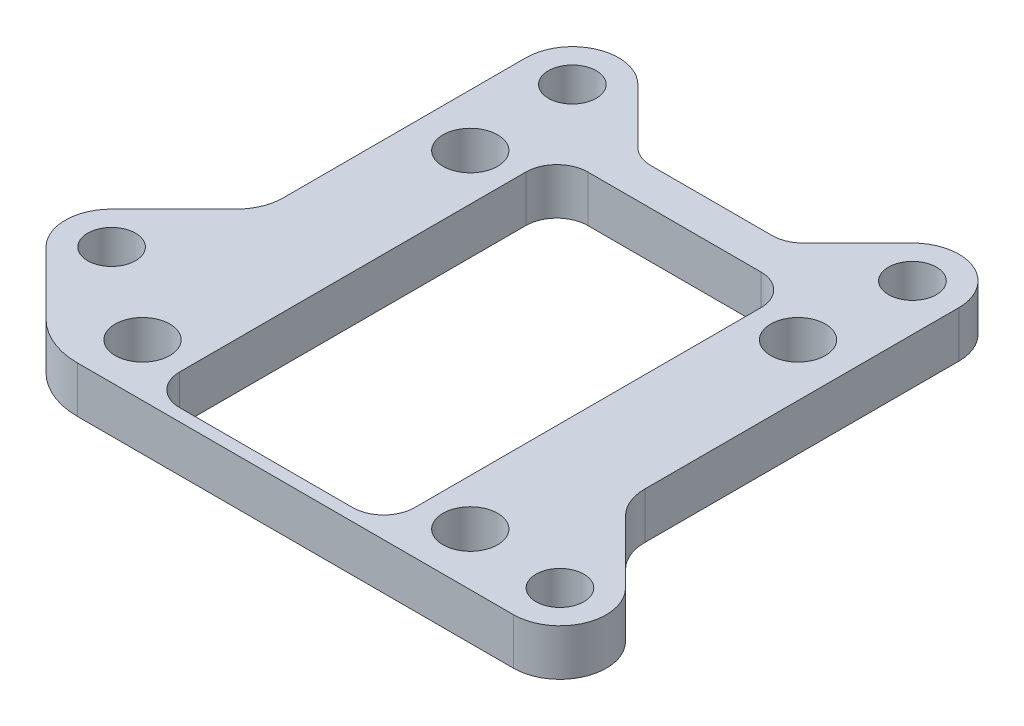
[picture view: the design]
ISO-10303-21;
HEADER;
FILE_DESCRIPTION(('STEP AP214'),'2;1');
FILE_NAME('part.step','',(''),(''),'','','');
FILE_SCHEMA(('AUTOMOTIVE_DESIGN { 1 0 10303 214 1 1 1 1 }'));
ENDSEC;
DATA;
#1=APPLICATION_CONTEXT('core data for automotive mechanical design processes');
#2=APPLICATION_PROTOCOL_DEFINITION('international standard','automotive_design',2000,#1);
#3=PRODUCT_CONTEXT('',#1,'mechanical');
#4=PRODUCT('Part','Part','',(#3));
#5=PRODUCT_RELATED_PRODUCT_CATEGORY('part','',(#4));
#6=PRODUCT_DEFINITION_FORMATION('','',#4);
#7=PRODUCT_DEFINITION_CONTEXT('part definition',#1,'design');
#8=PRODUCT_DEFINITION('design','',#6,#7);
#9=PRODUCT_DEFINITION_SHAPE('','',#8);
#10=(LENGTH_UNIT() NAMED_UNIT(*) SI_UNIT(.MILLI.,.METRE.));
#11=(NAMED_UNIT(*) PLANE_ANGLE_UNIT() SI_UNIT($,.RADIAN.));
#12=(NAMED_UNIT(*) SI_UNIT($,.STERADIAN.) SOLID_ANGLE_UNIT());
#13=UNCERTAINTY_MEASURE_WITH_UNIT(LENGTH_MEASURE(1.E-05),#10,'distance_accuracy_value','');
#14=(GEOMETRIC_REPRESENTATION_CONTEXT(3) GLOBAL_UNCERTAINTY_ASSIGNED_CONTEXT((#13)) GLOBAL_UNIT_ASSIGNED_CONTEXT((#10,
#11,#12)) REPRESENTATION_CONTEXT('',''));
#15=CARTESIAN_POINT('',(0.,0.,0.));
#16=DIRECTION('',(0.,0.,1.));
#17=DIRECTION('',(1.,0.,0.));
#18=AXIS2_PLACEMENT_3D('',#15,#16,#17);
#19=CARTESIAN_POINT('',(6.23717984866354,4.7625,-27.94));
#20=DIRECTION('',(0.,-1.,0.));
#21=DIRECTION('',(0.,0.,-1.));
#22=AXIS2_PLACEMENT_3D('',#19,#20,#21);
#23=PLANE('',#22);
#24=CARTESIAN_POINT('',(-17.4625,4.7625,-27.94));
#25=DIRECTION('',(0.,1.,0.));
#26=DIRECTION('',(0.,0.,1.));
#27=AXIS2_PLACEMENT_3D('',#24,#25,#26);
#28=CIRCLE('',#27,2.45744999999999);
#29=CARTESIAN_POINT('',(-17.4625,4.7625,-25.48255));
#30=VERTEX_POINT('',#29);
#31=EDGE_CURVE('E810',#30,#30,#28,.T.);
#32=ORIENTED_EDGE('',*,*,#31,.F.);
#33=EDGE_LOOP('',(#32));
#34=FACE_BOUND('',#33,.T.);
#35=CARTESIAN_POINT('',(17.4625,4.7625,-27.94));
#36=DIRECTION('',(0.,1.,0.));
#37=DIRECTION('',(0.,0.,1.));
#38=AXIS2_PLACEMENT_3D('',#35,#36,#37);
#39=CIRCLE('',#38,2.45744999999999);
#40=CARTESIAN_POINT('',(17.4625,4.7625,-25.48255));
#41=VERTEX_POINT('',#40);
#42=EDGE_CURVE('E812',#41,#41,#39,.T.);
#43=ORIENTED_EDGE('',*,*,#42,.F.);
#44=EDGE_LOOP('',(#43));
#45=FACE_BOUND('',#44,.T.);
#46=CARTESIAN_POINT('',(-26.67,4.7625,10.16));
#47=DIRECTION('',(0.,1.,0.));
#48=DIRECTION('',(0.,0.,1.));
#49=AXIS2_PLACEMENT_3D('',#46,#47,#48);
#50=CIRCLE('',#49,2.45744999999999);
#51=CARTESIAN_POINT('',(-26.67,4.7625,12.61745));
#52=VERTEX_POINT('',#51);
#53=EDGE_CURVE('E820',#52,#52,#50,.T.);
#54=ORIENTED_EDGE('',*,*,#53,.F.);
#55=EDGE_LOOP('',(#54));
#56=FACE_BOUND('',#55,.T.);
#57=CARTESIAN_POINT('',(26.67,4.7625,17.4625));
#58=DIRECTION('',(0.,1.,0.));
#59=DIRECTION('',(0.,0.,1.));
#60=AXIS2_PLACEMENT_3D('',#57,#58,#59);
#61=CIRCLE('',#60,2.45744999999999);
#62=CARTESIAN_POINT('',(26.67,4.7625,19.91995));
#63=VERTEX_POINT('',#62);
#64=EDGE_CURVE('E826',#63,#63,#61,.T.);
#65=ORIENTED_EDGE('',*,*,#64,.F.);
#66=EDGE_LOOP('',(#65));
#67=FACE_BOUND('',#66,.T.);
#68=CARTESIAN_POINT('',(-16.8275,4.7625,-16.8275));
#69=DIRECTION('',(0.,1.,0.));
#70=DIRECTION('',(0.,0.,1.));
#71=AXIS2_PLACEMENT_3D('',#68,#69,#70);
#72=CIRCLE('',#71,2.80669999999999);
#73=CARTESIAN_POINT('',(-16.8275,4.7625,-14.0208));
#74=VERTEX_POINT('',#73);
#75=EDGE_CURVE('E832',#74,#74,#72,.T.);
#76=ORIENTED_EDGE('',*,*,#75,.F.);
#77=EDGE_LOOP('',(#76));
#78=FACE_BOUND('',#77,.T.);
#79=CARTESIAN_POINT('',(16.8275,4.7625,16.8275));
#80=DIRECTION('',(0.,1.,0.));
#81=DIRECTION('',(0.,0.,1.));
#82=AXIS2_PLACEMENT_3D('',#79,#80,#81);
#83=CIRCLE('',#82,2.80669999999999);
#84=CARTESIAN_POINT('',(16.8275,4.7625,19.6342));
#85=VERTEX_POINT('',#84);
#86=EDGE_CURVE('E838',#85,#85,#83,.T.);
#87=ORIENTED_EDGE('',*,*,#86,.F.);
#88=EDGE_LOOP('',(#87));
#89=FACE_BOUND('',#88,.T.);
#90=CARTESIAN_POINT('',(16.8275,4.7625,-16.8275));
#91=DIRECTION('',(0.,1.,0.));
#92=DIRECTION('',(0.,0.,1.));
#93=AXIS2_PLACEMENT_3D('',#90,#91,#92);
#94=CIRCLE('',#93,2.80669999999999);
#95=CARTESIAN_POINT('',(16.8275,4.7625,-14.0208));
#96=VERTEX_POINT('',#95);
#97=EDGE_CURVE('E844',#96,#96,#94,.T.);
#98=ORIENTED_EDGE('',*,*,#97,.F.);
#99=EDGE_LOOP('',(#98));
#100=FACE_BOUND('',#99,.T.);
#101=CARTESIAN_POINT('',(6.23717984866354,4.7625,-27.94));
#102=DIRECTION('',(0.,-1.,0.));
#103=DIRECTION('',(0.,0.,-1.));
#104=AXIS2_PLACEMENT_3D('',#101,#102,#103);
#105=CIRCLE('',#104,3.175);
#106=CARTESIAN_POINT('',(8.48224387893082,4.7625,-25.6949359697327));
#107=VERTEX_POINT('',#106);
#108=CARTESIAN_POINT('',(6.23717984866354,4.7625,-24.765));
#109=VERTEX_POINT('',#108);
#110=EDGE_CURVE('E276',#107,#109,#105,.T.);
#111=ORIENTED_EDGE('',*,*,#110,.T.);
#112=DIRECTION('',(-1.,0.,0.));
#113=VECTOR('',#112,1.);
#114=CARTESIAN_POINT('',(-6.23717984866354,4.7625,-24.765));
#115=LINE('',#114,#113);
#116=CARTESIAN_POINT('',(-6.23717984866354,4.7625,-24.765));
#117=VERTEX_POINT('',#116);
#118=EDGE_CURVE('E279',#109,#117,#115,.T.);
#119=ORIENTED_EDGE('',*,*,#118,.T.);
#120=CARTESIAN_POINT('',(-6.23717984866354,4.7625,-27.94));
#121=DIRECTION('',(0.,-1.,0.));
#122=DIRECTION('',(0.,0.,1.));
#123=AXIS2_PLACEMENT_3D('',#120,#121,#122);
#124=CIRCLE('',#123,3.17500000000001);
#125=CARTESIAN_POINT('',(-8.48224387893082,4.7625,-25.6949359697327));
#126=VERTEX_POINT('',#125);
#127=EDGE_CURVE('E282',#117,#126,#124,.T.);
#128=ORIENTED_EDGE('',*,*,#127,.T.);
#129=DIRECTION('',(-0.707106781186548,0.,-0.707106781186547));
#130=VECTOR('',#129,1.);
#131=CARTESIAN_POINT('',(-8.48224387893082,4.7625,-25.6949359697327));
#132=LINE('',#131,#130);
#133=CARTESIAN_POINT('',(-14.0949039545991,4.7625,-31.3075960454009));
#134=VERTEX_POINT('',#133);
#135=EDGE_CURVE('E284',#126,#134,#132,.T.);
#136=ORIENTED_EDGE('',*,*,#135,.T.);
#137=CARTESIAN_POINT('',(-17.4625,4.7625,-27.94));
#138=DIRECTION('',(0.,1.,0.));
#139=DIRECTION('',(0.,0.,-1.));
#140=AXIS2_PLACEMENT_3D('',#137,#138,#139);
#141=CIRCLE('',#140,4.7625);
#142=CARTESIAN_POINT('',(-22.225,4.7625,-27.94));
#143=VERTEX_POINT('',#142);
#144=EDGE_CURVE('E286',#134,#143,#141,.T.);
#145=ORIENTED_EDGE('',*,*,#144,.T.);
#146=DIRECTION('',(0.,0.,1.));
#147=VECTOR('',#146,1.);
#148=CARTESIAN_POINT('',(-22.225,4.7625,-2.99288418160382));
#149=LINE('',#148,#147);
#150=CARTESIAN_POINT('',(-22.225,4.7625,-2.99288418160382));
#151=VERTEX_POINT('',#150);
#152=EDGE_CURVE('E288',#143,#151,#149,.T.);
#153=ORIENTED_EDGE('',*,*,#152,.T.);
#154=CARTESIAN_POINT('',(-26.9875,4.7625,-2.99288418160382));
#155=DIRECTION('',(0.,-1.,0.));
#156=DIRECTION('',(0.,0.,-1.));
#157=AXIS2_PLACEMENT_3D('',#154,#155,#156);
#158=CIRCLE('',#157,4.76249999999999);
#159=CARTESIAN_POINT('',(-23.619903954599,4.7625,0.374711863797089));
#160=VERTEX_POINT('',#159);
#161=EDGE_CURVE('E290',#151,#160,#158,.T.);
#162=ORIENTED_EDGE('',*,*,#161,.T.);
#163=DIRECTION('',(-0.707106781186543,0.,0.707106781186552));
#164=VECTOR('',#163,1.);
#165=CARTESIAN_POINT('',(-23.619903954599,4.7625,0.374711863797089));
#166=LINE('',#165,#164);
#167=CARTESIAN_POINT('',(-30.0375960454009,4.7625,6.79240395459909));
#168=VERTEX_POINT('',#167);
#169=EDGE_CURVE('E292',#160,#168,#166,.T.);
#170=ORIENTED_EDGE('',*,*,#169,.T.);
#171=CARTESIAN_POINT('',(-26.67,4.7625,10.16));
#172=DIRECTION('',(0.,1.,0.));
#173=DIRECTION('',(0.,0.,-1.));
#174=AXIS2_PLACEMENT_3D('',#171,#172,#173);
#175=CIRCLE('',#174,4.7625);
#176=CARTESIAN_POINT('',(-30.0375960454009,4.7625,13.5275960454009));
#177=VERTEX_POINT('',#176);
#178=EDGE_CURVE('E294',#168,#177,#175,.T.);
#179=ORIENTED_EDGE('',*,*,#178,.T.);
#180=DIRECTION('',(0.707106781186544,0.,0.707106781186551));
#181=VECTOR('',#180,1.);
#182=CARTESIAN_POINT('',(-30.0375960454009,4.7625,13.5275960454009));
#183=LINE('',#182,#181);
#184=CARTESIAN_POINT('',(-23.619903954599,4.7625,19.9452881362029));
#185=VERTEX_POINT('',#184);
#186=EDGE_CURVE('E296',#177,#185,#183,.T.);
#187=ORIENTED_EDGE('',*,*,#186,.T.);
#188=CARTESIAN_POINT('',(-18.1161926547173,4.7625,14.4415768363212));
#189=DIRECTION('',(0.,1.,0.));
#190=DIRECTION('',(0.,0.,-1.));
#191=AXIS2_PLACEMENT_3D('',#188,#189,#190);
#192=CIRCLE('',#191,7.78342316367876);
#193=CARTESIAN_POINT('',(-18.1161926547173,4.7625,22.225));
#194=VERTEX_POINT('',#193);
#195=EDGE_CURVE('E298',#185,#194,#192,.T.);
#196=ORIENTED_EDGE('',*,*,#195,.T.);
#197=DIRECTION('',(1.,0.,0.));
#198=VECTOR('',#197,1.);
#199=CARTESIAN_POINT('',(-18.1161926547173,4.7625,22.225));
#200=LINE('',#199,#198);
#201=CARTESIAN_POINT('',(26.67,4.7625,22.225));
#202=VERTEX_POINT('',#201);
#203=EDGE_CURVE('E300',#194,#202,#200,.T.);
#204=ORIENTED_EDGE('',*,*,#203,.T.);
#205=CARTESIAN_POINT('',(26.67,4.7625,17.4625));
#206=DIRECTION('',(0.,1.,0.));
#207=DIRECTION('',(0.,0.,1.));
#208=AXIS2_PLACEMENT_3D('',#205,#206,#207);
#209=CIRCLE('',#208,4.7625);
#210=CARTESIAN_POINT('',(30.037596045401,4.7625,14.0949039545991));
#211=VERTEX_POINT('',#210);
#212=EDGE_CURVE('E302',#202,#211,#209,.T.);
#213=ORIENTED_EDGE('',*,*,#212,.T.);
#214=DIRECTION('',(-0.707106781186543,0.,-0.707106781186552));
#215=VECTOR('',#214,1.);
#216=CARTESIAN_POINT('',(23.619903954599,4.7625,7.67721186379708));
#217=LINE('',#216,#215);
#218=CARTESIAN_POINT('',(23.619903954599,4.7625,7.67721186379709));
#219=VERTEX_POINT('',#218);
#220=EDGE_CURVE('E304',#211,#219,#217,.T.);
#221=ORIENTED_EDGE('',*,*,#220,.T.);
#222=CARTESIAN_POINT('',(26.9875,4.7625,4.30961581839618));
#223=DIRECTION('',(0.,-1.,0.));
#224=DIRECTION('',(0.,0.,-1.));
#225=AXIS2_PLACEMENT_3D('',#222,#223,#224);
#226=CIRCLE('',#225,4.7625);
#227=CARTESIAN_POINT('',(22.225,4.7625,4.30961581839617));
#228=VERTEX_POINT('',#227);
#229=EDGE_CURVE('E306',#219,#228,#226,.T.);
#230=ORIENTED_EDGE('',*,*,#229,.T.);
#231=DIRECTION('',(0.,0.,-1.));
#232=VECTOR('',#231,1.);
#233=CARTESIAN_POINT('',(22.225,4.7625,4.30961581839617));
#234=LINE('',#233,#232);
#235=CARTESIAN_POINT('',(22.225,4.7625,-27.94));
#236=VERTEX_POINT('',#235);
#237=EDGE_CURVE('E308',#228,#236,#234,.T.);
#238=ORIENTED_EDGE('',*,*,#237,.T.);
#239=CARTESIAN_POINT('',(17.4625,4.7625,-27.94));
#240=DIRECTION('',(0.,1.,0.));
#241=DIRECTION('',(0.,0.,-1.));
#242=AXIS2_PLACEMENT_3D('',#239,#240,#241);
#243=CIRCLE('',#242,4.7625);
#244=CARTESIAN_POINT('',(14.0949039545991,4.7625,-31.3075960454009));
#245=VERTEX_POINT('',#244);
#246=EDGE_CURVE('E310',#236,#245,#243,.T.);
#247=ORIENTED_EDGE('',*,*,#246,.T.);
#248=DIRECTION('',(-0.707106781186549,0.,0.707106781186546));
#249=VECTOR('',#248,1.);
#250=CARTESIAN_POINT('',(8.48224387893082,4.7625,-25.6949359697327));
#251=LINE('',#250,#249);
#252=EDGE_CURVE('E312',#245,#107,#251,.T.);
#253=ORIENTED_EDGE('',*,*,#252,.T.);
#254=EDGE_LOOP('',(#111,#119,#128,#136,#145,#153,#162,#170,#179,#187,#196,#204,#213,#221,#230,
#238,#247,#253));
#255=FACE_BOUND('',#254,.T.);
#256=CARTESIAN_POINT('',(-8.89,4.7625,-17.78));
#257=DIRECTION('',(0.,1.,0.));
#258=DIRECTION('',(0.,0.,-1.));
#259=AXIS2_PLACEMENT_3D('',#256,#257,#258);
#260=CIRCLE('',#259,3.175);
#261=CARTESIAN_POINT('',(-8.88999999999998,4.7625,-20.955));
#262=VERTEX_POINT('',#261);
#263=CARTESIAN_POINT('',(-12.065,4.7625,-17.78));
#264=VERTEX_POINT('',#263);
#265=EDGE_CURVE('E208',#262,#264,#260,.T.);
#266=ORIENTED_EDGE('',*,*,#265,.F.);
#267=DIRECTION('',(-1.,0.,0.));
#268=VECTOR('',#267,1.);
#269=CARTESIAN_POINT('',(-8.88999999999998,4.7625,-20.955));
#270=LINE('',#269,#268);
#271=CARTESIAN_POINT('',(8.88999999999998,4.7625,-20.955));
#272=VERTEX_POINT('',#271);
#273=EDGE_CURVE('E243',#272,#262,#270,.T.);
#274=ORIENTED_EDGE('',*,*,#273,.F.);
#275=CARTESIAN_POINT('',(8.89,4.7625,-17.78));
#276=DIRECTION('',(0.,1.,0.));
#277=DIRECTION('',(0.,0.,-1.));
#278=AXIS2_PLACEMENT_3D('',#275,#276,#277);
#279=CIRCLE('',#278,3.175);
#280=CARTESIAN_POINT('',(12.065,4.7625,-17.78));
#281=VERTEX_POINT('',#280);
#282=EDGE_CURVE('E241',#281,#272,#279,.T.);
#283=ORIENTED_EDGE('',*,*,#282,.F.);
#284=DIRECTION('',(0.,0.,-1.));
#285=VECTOR('',#284,1.);
#286=CARTESIAN_POINT('',(12.065,4.7625,17.78));
#287=LINE('',#286,#285);
#288=CARTESIAN_POINT('',(12.065,4.7625,17.78));
#289=VERTEX_POINT('',#288);
#290=EDGE_CURVE('E239',#289,#281,#287,.T.);
#291=ORIENTED_EDGE('',*,*,#290,.F.);
#292=CARTESIAN_POINT('',(8.89,4.7625,17.78));
#293=DIRECTION('',(0.,1.,0.));
#294=DIRECTION('',(0.,0.,1.));
#295=AXIS2_PLACEMENT_3D('',#292,#293,#294);
#296=CIRCLE('',#295,3.175);
#297=CARTESIAN_POINT('',(8.88999999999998,4.7625,20.955));
#298=VERTEX_POINT('',#297);
#299=EDGE_CURVE('E237',#298,#289,#296,.T.);
#300=ORIENTED_EDGE('',*,*,#299,.F.);
#301=DIRECTION('',(1.,0.,0.));
#302=VECTOR('',#301,1.);
#303=CARTESIAN_POINT('',(-8.88999999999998,4.7625,20.955));
#304=LINE('',#303,#302);
#305=CARTESIAN_POINT('',(-8.88999999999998,4.7625,20.955));
#306=VERTEX_POINT('',#305);
#307=EDGE_CURVE('E232',#306,#298,#304,.T.);
#308=ORIENTED_EDGE('',*,*,#307,.F.);
#309=CARTESIAN_POINT('',(-8.89,4.7625,17.78));
#310=DIRECTION('',(0.,1.,0.));
#311=DIRECTION('',(0.,0.,-1.));
#312=AXIS2_PLACEMENT_3D('',#309,#310,#311);
#313=CIRCLE('',#312,3.175);
#314=CARTESIAN_POINT('',(-12.065,4.7625,17.78));
#315=VERTEX_POINT('',#314);
#316=EDGE_CURVE('E230',#315,#306,#313,.T.);
#317=ORIENTED_EDGE('',*,*,#316,.F.);
#318=DIRECTION('',(0.,0.,1.));
#319=VECTOR('',#318,1.);
#320=CARTESIAN_POINT('',(-12.065,4.7625,17.78));
#321=LINE('',#320,#319);
#322=EDGE_CURVE('E216',#264,#315,#321,.T.);
#323=ORIENTED_EDGE('',*,*,#322,.F.);
#324=EDGE_LOOP('',(#266,#274,#283,#291,#300,#308,#317,#323));
#325=FACE_BOUND('',#324,.T.);
#326=CARTESIAN_POINT('',(-16.8275,4.7625,16.8275));
#327=DIRECTION('',(0.,1.,0.));
#328=DIRECTION('',(0.,0.,1.));
#329=AXIS2_PLACEMENT_3D('',#326,#327,#328);
#330=CIRCLE('',#329,2.80669999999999);
#331=CARTESIAN_POINT('',(-16.8275,4.7625,19.6342));
#332=VERTEX_POINT('',#331);
#333=EDGE_CURVE('E850',#332,#332,#330,.T.);
#334=ORIENTED_EDGE('',*,*,#333,.F.);
#335=EDGE_LOOP('',(#334));
#336=FACE_BOUND('',#335,.T.);
#337=ADVANCED_FACE('F35',(#34,#45,#56,#67,#78,#89,#100,#255,#325,#336),#23,.F.);
#338=CARTESIAN_POINT('',(6.23717984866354,0.,-27.94));
#339=DIRECTION('',(0.,-1.,0.));
#340=DIRECTION('',(0.,0.,-1.));
#341=AXIS2_PLACEMENT_3D('',#338,#339,#340);
#342=PLANE('',#341);
#343=CARTESIAN_POINT('',(-17.4625,0.,-27.94));
#344=DIRECTION('',(0.,1.,0.));
#345=DIRECTION('',(0.,0.,1.));
#346=AXIS2_PLACEMENT_3D('',#343,#344,#345);
#347=CIRCLE('',#346,2.45745);
#348=CARTESIAN_POINT('',(-17.4625,0.,-25.48255));
#349=VERTEX_POINT('',#348);
#350=EDGE_CURVE('E808',#349,#349,#347,.T.);
#351=ORIENTED_EDGE('',*,*,#350,.T.);
#352=EDGE_LOOP('',(#351));
#353=FACE_BOUND('',#352,.T.);
#354=CARTESIAN_POINT('',(17.4625,0.,-27.94));
#355=DIRECTION('',(0.,1.,0.));
#356=DIRECTION('',(0.,0.,1.));
#357=AXIS2_PLACEMENT_3D('',#354,#355,#356);
#358=CIRCLE('',#357,2.45745);
#359=CARTESIAN_POINT('',(17.4625,0.,-25.48255));
#360=VERTEX_POINT('',#359);
#361=EDGE_CURVE('E817',#360,#360,#358,.T.);
#362=ORIENTED_EDGE('',*,*,#361,.T.);
#363=EDGE_LOOP('',(#362));
#364=FACE_BOUND('',#363,.T.);
#365=CARTESIAN_POINT('',(-26.67,0.,10.16));
#366=DIRECTION('',(0.,1.,0.));
#367=DIRECTION('',(0.,0.,1.));
#368=AXIS2_PLACEMENT_3D('',#365,#366,#367);
#369=CIRCLE('',#368,2.45745);
#370=CARTESIAN_POINT('',(-26.67,0.,12.61745));
#371=VERTEX_POINT('',#370);
#372=EDGE_CURVE('E823',#371,#371,#369,.T.);
#373=ORIENTED_EDGE('',*,*,#372,.T.);
#374=EDGE_LOOP('',(#373));
#375=FACE_BOUND('',#374,.T.);
#376=CARTESIAN_POINT('',(26.67,0.,17.4625));
#377=DIRECTION('',(0.,1.,0.));
#378=DIRECTION('',(0.,0.,1.));
#379=AXIS2_PLACEMENT_3D('',#376,#377,#378);
#380=CIRCLE('',#379,2.45745);
#381=CARTESIAN_POINT('',(26.67,0.,19.91995));
#382=VERTEX_POINT('',#381);
#383=EDGE_CURVE('E829',#382,#382,#380,.T.);
#384=ORIENTED_EDGE('',*,*,#383,.T.);
#385=EDGE_LOOP('',(#384));
#386=FACE_BOUND('',#385,.T.);
#387=CARTESIAN_POINT('',(-16.8275,0.,-16.8275));
#388=DIRECTION('',(0.,1.,0.));
#389=DIRECTION('',(0.,0.,1.));
#390=AXIS2_PLACEMENT_3D('',#387,#388,#389);
#391=CIRCLE('',#390,2.8067);
#392=CARTESIAN_POINT('',(-16.8275,0.,-14.0208));
#393=VERTEX_POINT('',#392);
#394=EDGE_CURVE('E835',#393,#393,#391,.T.);
#395=ORIENTED_EDGE('',*,*,#394,.T.);
#396=EDGE_LOOP('',(#395));
#397=FACE_BOUND('',#396,.T.);
#398=CARTESIAN_POINT('',(16.8275,0.,16.8275));
#399=DIRECTION('',(0.,1.,0.));
#400=DIRECTION('',(0.,0.,1.));
#401=AXIS2_PLACEMENT_3D('',#398,#399,#400);
#402=CIRCLE('',#401,2.8067);
#403=CARTESIAN_POINT('',(16.8275,0.,19.6342));
#404=VERTEX_POINT('',#403);
#405=EDGE_CURVE('E841',#404,#404,#402,.T.);
#406=ORIENTED_EDGE('',*,*,#405,.T.);
#407=EDGE_LOOP('',(#406));
#408=FACE_BOUND('',#407,.T.);
#409=CARTESIAN_POINT('',(16.8275,0.,-16.8275));
#410=DIRECTION('',(0.,1.,0.));
#411=DIRECTION('',(0.,0.,1.));
#412=AXIS2_PLACEMENT_3D('',#409,#410,#411);
#413=CIRCLE('',#412,2.8067);
#414=CARTESIAN_POINT('',(16.8275,0.,-14.0208));
#415=VERTEX_POINT('',#414);
#416=EDGE_CURVE('E847',#415,#415,#413,.T.);
#417=ORIENTED_EDGE('',*,*,#416,.T.);
#418=EDGE_LOOP('',(#417));
#419=FACE_BOUND('',#418,.T.);
#420=DIRECTION('',(-1.,0.,0.));
#421=VECTOR('',#420,1.);
#422=CARTESIAN_POINT('',(-8.88999999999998,0.,-20.955));
#423=LINE('',#422,#421);
#424=CARTESIAN_POINT('',(8.88999999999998,0.,-20.955));
#425=VERTEX_POINT('',#424);
#426=CARTESIAN_POINT('',(-8.88999999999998,0.,-20.955));
#427=VERTEX_POINT('',#426);
#428=EDGE_CURVE('E217',#425,#427,#423,.T.);
#429=ORIENTED_EDGE('',*,*,#428,.T.);
#430=CARTESIAN_POINT('',(-8.89,0.,-17.78));
#431=DIRECTION('',(0.,1.,0.));
#432=DIRECTION('',(0.,0.,-1.));
#433=AXIS2_PLACEMENT_3D('',#430,#431,#432);
#434=CIRCLE('',#433,3.175);
#435=CARTESIAN_POINT('',(-12.065,0.,-17.78));
#436=VERTEX_POINT('',#435);
#437=EDGE_CURVE('E58',#427,#436,#434,.T.);
#438=ORIENTED_EDGE('',*,*,#437,.T.);
#439=DIRECTION('',(0.,0.,1.));
#440=VECTOR('',#439,1.);
#441=CARTESIAN_POINT('',(-12.065,0.,17.78));
#442=LINE('',#441,#440);
#443=CARTESIAN_POINT('',(-12.065,0.,17.78));
#444=VERTEX_POINT('',#443);
#445=EDGE_CURVE('E223',#436,#444,#442,.T.);
#446=ORIENTED_EDGE('',*,*,#445,.T.);
#447=CARTESIAN_POINT('',(-8.89,0.,17.78));
#448=DIRECTION('',(0.,1.,0.));
#449=DIRECTION('',(0.,0.,-1.));
#450=AXIS2_PLACEMENT_3D('',#447,#448,#449);
#451=CIRCLE('',#450,3.175);
#452=CARTESIAN_POINT('',(-8.88999999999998,0.,20.955));
#453=VERTEX_POINT('',#452);
#454=EDGE_CURVE('E248',#444,#453,#451,.T.);
#455=ORIENTED_EDGE('',*,*,#454,.T.);
#456=DIRECTION('',(1.,0.,0.));
#457=VECTOR('',#456,1.);
#458=CARTESIAN_POINT('',(-8.88999999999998,0.,20.955));
#459=LINE('',#458,#457);
#460=CARTESIAN_POINT('',(8.88999999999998,0.,20.955));
#461=VERTEX_POINT('',#460);
#462=EDGE_CURVE('E251',#453,#461,#459,.T.);
#463=ORIENTED_EDGE('',*,*,#462,.T.);
#464=CARTESIAN_POINT('',(8.89,0.,17.78));
#465=DIRECTION('',(0.,1.,0.));
#466=DIRECTION('',(0.,0.,1.));
#467=AXIS2_PLACEMENT_3D('',#464,#465,#466);
#468=CIRCLE('',#467,3.175);
#469=CARTESIAN_POINT('',(12.065,0.,17.78));
#470=VERTEX_POINT('',#469);
#471=EDGE_CURVE('E254',#461,#470,#468,.T.);
#472=ORIENTED_EDGE('',*,*,#471,.T.);
#473=DIRECTION('',(0.,0.,-1.));
#474=VECTOR('',#473,1.);
#475=CARTESIAN_POINT('',(12.065,0.,17.78));
#476=LINE('',#475,#474);
#477=CARTESIAN_POINT('',(12.065,0.,-17.78));
#478=VERTEX_POINT('',#477);
#479=EDGE_CURVE('E257',#470,#478,#476,.T.);
#480=ORIENTED_EDGE('',*,*,#479,.T.);
#481=CARTESIAN_POINT('',(8.89,0.,-17.78));
#482=DIRECTION('',(0.,1.,0.));
#483=DIRECTION('',(0.,0.,-1.));
#484=AXIS2_PLACEMENT_3D('',#481,#482,#483);
#485=CIRCLE('',#484,3.175);
#486=EDGE_CURVE('E260',#478,#425,#485,.T.);
#487=ORIENTED_EDGE('',*,*,#486,.T.);
#488=EDGE_LOOP('',(#429,#438,#446,#455,#463,#472,#480,#487));
#489=FACE_BOUND('',#488,.T.);
#490=CARTESIAN_POINT('',(6.23717984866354,0.,-27.94));
#491=DIRECTION('',(0.,-1.,0.));
#492=DIRECTION('',(0.,0.,-1.));
#493=AXIS2_PLACEMENT_3D('',#490,#491,#492);
#494=CIRCLE('',#493,3.175);
#495=CARTESIAN_POINT('',(8.48224387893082,0.,-25.6949359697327));
#496=VERTEX_POINT('',#495);
#497=CARTESIAN_POINT('',(6.23717984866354,0.,-24.765));
#498=VERTEX_POINT('',#497);
#499=EDGE_CURVE('E224',#496,#498,#494,.T.);
#500=ORIENTED_EDGE('',*,*,#499,.F.);
#501=DIRECTION('',(-0.707106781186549,0.,0.707106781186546));
#502=VECTOR('',#501,1.);
#503=CARTESIAN_POINT('',(8.48224387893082,0.,-25.6949359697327));
#504=LINE('',#503,#502);
#505=CARTESIAN_POINT('',(14.0949039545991,0.,-31.3075960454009));
#506=VERTEX_POINT('',#505);
#507=EDGE_CURVE('E280',#506,#496,#504,.T.);
#508=ORIENTED_EDGE('',*,*,#507,.F.);
#509=CARTESIAN_POINT('',(17.4625,0.,-27.94));
#510=DIRECTION('',(0.,1.,0.));
#511=DIRECTION('',(0.,0.,-1.));
#512=AXIS2_PLACEMENT_3D('',#509,#510,#511);
#513=CIRCLE('',#512,4.7625);
#514=CARTESIAN_POINT('',(22.225,0.,-27.94));
#515=VERTEX_POINT('',#514);
#516=EDGE_CURVE('E347',#515,#506,#513,.T.);
#517=ORIENTED_EDGE('',*,*,#516,.F.);
#518=DIRECTION('',(0.,0.,-1.));
#519=VECTOR('',#518,1.);
#520=CARTESIAN_POINT('',(22.225,0.,4.30961581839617));
#521=LINE('',#520,#519);
#522=CARTESIAN_POINT('',(22.225,0.,4.30961581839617));
#523=VERTEX_POINT('',#522);
#524=EDGE_CURVE('E345',#523,#515,#521,.T.);
#525=ORIENTED_EDGE('',*,*,#524,.F.);
#526=CARTESIAN_POINT('',(26.9875,0.,4.30961581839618));
#527=DIRECTION('',(0.,-1.,0.));
#528=DIRECTION('',(0.,0.,-1.));
#529=AXIS2_PLACEMENT_3D('',#526,#527,#528);
#530=CIRCLE('',#529,4.7625);
#531=CARTESIAN_POINT('',(23.619903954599,0.,7.67721186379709));
#532=VERTEX_POINT('',#531);
#533=EDGE_CURVE('E343',#532,#523,#530,.T.);
#534=ORIENTED_EDGE('',*,*,#533,.F.);
#535=DIRECTION('',(-0.707106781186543,0.,-0.707106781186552));
#536=VECTOR('',#535,1.);
#537=CARTESIAN_POINT('',(23.619903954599,0.,7.67721186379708));
#538=LINE('',#537,#536);
#539=CARTESIAN_POINT('',(30.037596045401,0.,14.0949039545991));
#540=VERTEX_POINT('',#539);
#541=EDGE_CURVE('E341',#540,#532,#538,.T.);
#542=ORIENTED_EDGE('',*,*,#541,.F.);
#543=CARTESIAN_POINT('',(26.67,0.,17.4625));
#544=DIRECTION('',(0.,1.,0.));
#545=DIRECTION('',(0.,0.,1.));
#546=AXIS2_PLACEMENT_3D('',#543,#544,#545);
#547=CIRCLE('',#546,4.7625);
#548=CARTESIAN_POINT('',(26.67,0.,22.225));
#549=VERTEX_POINT('',#548);
#550=EDGE_CURVE('E339',#549,#540,#547,.T.);
#551=ORIENTED_EDGE('',*,*,#550,.F.);
#552=DIRECTION('',(1.,0.,0.));
#553=VECTOR('',#552,1.);
#554=CARTESIAN_POINT('',(-18.1161926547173,0.,22.225));
#555=LINE('',#554,#553);
#556=CARTESIAN_POINT('',(-18.1161926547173,0.,22.225));
#557=VERTEX_POINT('',#556);
#558=EDGE_CURVE('E337',#557,#549,#555,.T.);
#559=ORIENTED_EDGE('',*,*,#558,.F.);
#560=CARTESIAN_POINT('',(-18.1161926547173,0.,14.4415768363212));
#561=DIRECTION('',(0.,1.,0.));
#562=DIRECTION('',(0.,0.,-1.));
#563=AXIS2_PLACEMENT_3D('',#560,#561,#562);
#564=CIRCLE('',#563,7.78342316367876);
#565=CARTESIAN_POINT('',(-23.619903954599,0.,19.9452881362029));
#566=VERTEX_POINT('',#565);
#567=EDGE_CURVE('E335',#566,#557,#564,.T.);
#568=ORIENTED_EDGE('',*,*,#567,.F.);
#569=DIRECTION('',(0.707106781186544,0.,0.707106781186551));
#570=VECTOR('',#569,1.);
#571=CARTESIAN_POINT('',(-30.0375960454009,0.,13.5275960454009));
#572=LINE('',#571,#570);
#573=CARTESIAN_POINT('',(-30.0375960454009,0.,13.5275960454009));
#574=VERTEX_POINT('',#573);
#575=EDGE_CURVE('E333',#574,#566,#572,.T.);
#576=ORIENTED_EDGE('',*,*,#575,.F.);
#577=CARTESIAN_POINT('',(-26.67,0.,10.16));
#578=DIRECTION('',(0.,1.,0.));
#579=DIRECTION('',(0.,0.,-1.));
#580=AXIS2_PLACEMENT_3D('',#577,#578,#579);
#581=CIRCLE('',#580,4.7625);
#582=CARTESIAN_POINT('',(-30.0375960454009,0.,6.79240395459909));
#583=VERTEX_POINT('',#582);
#584=EDGE_CURVE('E331',#583,#574,#581,.T.);
#585=ORIENTED_EDGE('',*,*,#584,.F.);
#586=DIRECTION('',(-0.707106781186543,0.,0.707106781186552));
#587=VECTOR('',#586,1.);
#588=CARTESIAN_POINT('',(-23.619903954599,0.,0.374711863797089));
#589=LINE('',#588,#587);
#590=CARTESIAN_POINT('',(-23.619903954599,0.,0.374711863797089));
#591=VERTEX_POINT('',#590);
#592=EDGE_CURVE('E329',#591,#583,#589,.T.);
#593=ORIENTED_EDGE('',*,*,#592,.F.);
#594=CARTESIAN_POINT('',(-26.9875,0.,-2.99288418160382));
#595=DIRECTION('',(0.,-1.,0.));
#596=DIRECTION('',(0.,0.,-1.));
#597=AXIS2_PLACEMENT_3D('',#594,#595,#596);
#598=CIRCLE('',#597,4.76249999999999);
#599=CARTESIAN_POINT('',(-22.225,0.,-2.99288418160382));
#600=VERTEX_POINT('',#599);
#601=EDGE_CURVE('E327',#600,#591,#598,.T.);
#602=ORIENTED_EDGE('',*,*,#601,.F.);
#603=DIRECTION('',(0.,0.,1.));
#604=VECTOR('',#603,1.);
#605=CARTESIAN_POINT('',(-22.225,0.,-2.99288418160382));
#606=LINE('',#605,#604);
#607=CARTESIAN_POINT('',(-22.225,0.,-27.94));
#608=VERTEX_POINT('',#607);
#609=EDGE_CURVE('E325',#608,#600,#606,.T.);
#610=ORIENTED_EDGE('',*,*,#609,.F.);
#611=CARTESIAN_POINT('',(-17.4625,0.,-27.94));
#612=DIRECTION('',(0.,1.,0.));
#613=DIRECTION('',(0.,0.,-1.));
#614=AXIS2_PLACEMENT_3D('',#611,#612,#613);
#615=CIRCLE('',#614,4.7625);
#616=CARTESIAN_POINT('',(-14.0949039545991,0.,-31.3075960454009));
#617=VERTEX_POINT('',#616);
#618=EDGE_CURVE('E323',#617,#608,#615,.T.);
#619=ORIENTED_EDGE('',*,*,#618,.F.);
#620=DIRECTION('',(-0.707106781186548,0.,-0.707106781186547));
#621=VECTOR('',#620,1.);
#622=CARTESIAN_POINT('',(-8.48224387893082,0.,-25.6949359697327));
#623=LINE('',#622,#621);
#624=CARTESIAN_POINT('',(-8.48224387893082,0.,-25.6949359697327));
#625=VERTEX_POINT('',#624);
#626=EDGE_CURVE('E321',#625,#617,#623,.T.);
#627=ORIENTED_EDGE('',*,*,#626,.F.);
#628=CARTESIAN_POINT('',(-6.23717984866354,0.,-27.94));
#629=DIRECTION('',(0.,-1.,0.));
#630=DIRECTION('',(0.,0.,1.));
#631=AXIS2_PLACEMENT_3D('',#628,#629,#630);
#632=CIRCLE('',#631,3.17500000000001);
#633=CARTESIAN_POINT('',(-6.23717984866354,0.,-24.765));
#634=VERTEX_POINT('',#633);
#635=EDGE_CURVE('E319',#634,#625,#632,.T.);
#636=ORIENTED_EDGE('',*,*,#635,.F.);
#637=DIRECTION('',(-1.,0.,0.));
#638=VECTOR('',#637,1.);
#639=CARTESIAN_POINT('',(-6.23717984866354,0.,-24.765));
#640=LINE('',#639,#638);
#641=EDGE_CURVE('E317',#498,#634,#640,.T.);
#642=ORIENTED_EDGE('',*,*,#641,.F.);
#643=EDGE_LOOP('',(#500,#508,#517,#525,#534,#542,#551,#559,#568,#576,#585,#593,#602,#610,#619,
#627,#636,#642));
#644=FACE_BOUND('',#643,.T.);
#645=CARTESIAN_POINT('',(-16.8275,0.,16.8275));
#646=DIRECTION('',(0.,1.,0.));
#647=DIRECTION('',(0.,0.,1.));
#648=AXIS2_PLACEMENT_3D('',#645,#646,#647);
#649=CIRCLE('',#648,2.8067);
#650=CARTESIAN_POINT('',(-16.8275,0.,19.6342));
#651=VERTEX_POINT('',#650);
#652=EDGE_CURVE('E246',#651,#651,#649,.T.);
#653=ORIENTED_EDGE('',*,*,#652,.T.);
#654=EDGE_LOOP('',(#653));
#655=FACE_BOUND('',#654,.T.);
#656=ADVANCED_FACE('F407',(#353,#364,#375,#386,#397,#408,#419,#489,#644,#655),#342,.T.);
#657=CARTESIAN_POINT('',(6.23717984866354,4.7625,-27.94));
#658=DIRECTION('',(0.,-1.,0.));
#659=DIRECTION('',(0.,0.,-1.));
#660=AXIS2_PLACEMENT_3D('',#657,#658,#659);
#661=CYLINDRICAL_SURFACE('',#660,3.175);
#662=ORIENTED_EDGE('',*,*,#499,.T.);
#663=DIRECTION('',(0.,-1.,0.));
#664=VECTOR('',#663,1.);
#665=CARTESIAN_POINT('',(6.23717984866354,4.7625,-24.765));
#666=LINE('',#665,#664);
#667=EDGE_CURVE('E11',#109,#498,#666,.T.);
#668=ORIENTED_EDGE('',*,*,#667,.F.);
#669=ORIENTED_EDGE('',*,*,#110,.F.);
#670=DIRECTION('',(0.,-1.,0.));
#671=VECTOR('',#670,1.);
#672=CARTESIAN_POINT('',(8.48224387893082,4.7625,-25.6949359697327));
#673=LINE('',#672,#671);
#674=EDGE_CURVE('E314',#107,#496,#673,.T.);
#675=ORIENTED_EDGE('',*,*,#674,.T.);
#676=EDGE_LOOP('',(#662,#668,#669,#675));
#677=FACE_BOUND('',#676,.T.);
#678=ADVANCED_FACE('F37',(#677),#661,.F.);
#679=CARTESIAN_POINT('',(-6.23717984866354,4.7625,-24.765));
#680=DIRECTION('',(0.,0.,1.));
#681=DIRECTION('',(1.,0.,0.));
#682=AXIS2_PLACEMENT_3D('',#679,#680,#681);
#683=PLANE('',#682);
#684=ORIENTED_EDGE('',*,*,#641,.T.);
#685=DIRECTION('',(0.,-1.,0.));
#686=VECTOR('',#685,1.);
#687=CARTESIAN_POINT('',(-6.23717984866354,4.7625,-24.765));
#688=LINE('',#687,#686);
#689=EDGE_CURVE('E43',#117,#634,#688,.T.);
#690=ORIENTED_EDGE('',*,*,#689,.F.);
#691=ORIENTED_EDGE('',*,*,#118,.F.);
#692=ORIENTED_EDGE('',*,*,#667,.T.);
#693=EDGE_LOOP('',(#684,#690,#691,#692));
#694=FACE_BOUND('',#693,.T.);
#695=ADVANCED_FACE('F424',(#694),#683,.F.);
#696=CARTESIAN_POINT('',(-6.23717984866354,4.7625,-27.94));
#697=DIRECTION('',(0.,-1.,0.));
#698=DIRECTION('',(0.,0.,-1.));
#699=AXIS2_PLACEMENT_3D('',#696,#697,#698);
#700=CYLINDRICAL_SURFACE('',#699,3.17500000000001);
#701=ORIENTED_EDGE('',*,*,#635,.T.);
#702=DIRECTION('',(0.,-1.,0.));
#703=VECTOR('',#702,1.);
#704=CARTESIAN_POINT('',(-8.48224387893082,4.7625,-25.6949359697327));
#705=LINE('',#704,#703);
#706=EDGE_CURVE('E394',#126,#625,#705,.T.);
#707=ORIENTED_EDGE('',*,*,#706,.F.);
#708=ORIENTED_EDGE('',*,*,#127,.F.);
#709=ORIENTED_EDGE('',*,*,#689,.T.);
#710=EDGE_LOOP('',(#701,#707,#708,#709));
#711=FACE_BOUND('',#710,.T.);
#712=ADVANCED_FACE('F401',(#711),#700,.F.);
#713=CARTESIAN_POINT('',(-8.48224387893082,4.7625,-25.6949359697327));
#714=DIRECTION('',(-0.707106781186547,0.,0.707106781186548));
#715=DIRECTION('',(0.707106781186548,0.,0.707106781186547));
#716=AXIS2_PLACEMENT_3D('',#713,#714,#715);
#717=PLANE('',#716);
#718=ORIENTED_EDGE('',*,*,#626,.T.);
#719=DIRECTION('',(0.,-1.,0.));
#720=VECTOR('',#719,1.);
#721=CARTESIAN_POINT('',(-14.0949039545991,4.7625,-31.3075960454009));
#722=LINE('',#721,#720);
#723=EDGE_CURVE('E391',#134,#617,#722,.T.);
#724=ORIENTED_EDGE('',*,*,#723,.F.);
#725=ORIENTED_EDGE('',*,*,#135,.F.);
#726=ORIENTED_EDGE('',*,*,#706,.T.);
#727=EDGE_LOOP('',(#718,#724,#725,#726));
#728=FACE_BOUND('',#727,.T.);
#729=ADVANCED_FACE('F413',(#728),#717,.F.);
#730=CARTESIAN_POINT('',(-17.4625,4.7625,-27.94));
#731=DIRECTION('',(0.,-1.,0.));
#732=DIRECTION('',(0.,0.,-1.));
#733=AXIS2_PLACEMENT_3D('',#730,#731,#732);
#734=CYLINDRICAL_SURFACE('',#733,4.7625);
#735=ORIENTED_EDGE('',*,*,#618,.T.);
#736=DIRECTION('',(0.,-1.,0.));
#737=VECTOR('',#736,1.);
#738=CARTESIAN_POINT('',(-22.225,4.7625,-27.94));
#739=LINE('',#738,#737);
#740=EDGE_CURVE('E388',#143,#608,#739,.T.);
#741=ORIENTED_EDGE('',*,*,#740,.F.);
#742=ORIENTED_EDGE('',*,*,#144,.F.);
#743=ORIENTED_EDGE('',*,*,#723,.T.);
#744=EDGE_LOOP('',(#735,#741,#742,#743));
#745=FACE_BOUND('',#744,.T.);
#746=ADVANCED_FACE('F417',(#745),#734,.T.);
#747=CARTESIAN_POINT('',(-22.225,4.7625,-2.99288418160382));
#748=DIRECTION('',(1.,0.,0.));
#749=DIRECTION('',(0.,0.,-1.));
#750=AXIS2_PLACEMENT_3D('',#747,#748,#749);
#751=PLANE('',#750);
#752=ORIENTED_EDGE('',*,*,#609,.T.);
#753=DIRECTION('',(0.,-1.,0.));
#754=VECTOR('',#753,1.);
#755=CARTESIAN_POINT('',(-22.225,4.7625,-2.99288418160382));
#756=LINE('',#755,#754);
#757=EDGE_CURVE('E385',#151,#600,#756,.T.);
#758=ORIENTED_EDGE('',*,*,#757,.F.);
#759=ORIENTED_EDGE('',*,*,#152,.F.);
#760=ORIENTED_EDGE('',*,*,#740,.T.);
#761=EDGE_LOOP('',(#752,#758,#759,#760));
#762=FACE_BOUND('',#761,.T.);
#763=ADVANCED_FACE('F487',(#762),#751,.F.);
#764=CARTESIAN_POINT('',(-26.9875,4.7625,-2.99288418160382));
#765=DIRECTION('',(0.,-1.,0.));
#766=DIRECTION('',(0.,0.,-1.));
#767=AXIS2_PLACEMENT_3D('',#764,#765,#766);
#768=CYLINDRICAL_SURFACE('',#767,4.76249999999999);
#769=ORIENTED_EDGE('',*,*,#601,.T.);
#770=DIRECTION('',(0.,-1.,0.));
#771=VECTOR('',#770,1.);
#772=CARTESIAN_POINT('',(-23.619903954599,4.7625,0.374711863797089));
#773=LINE('',#772,#771);
#774=EDGE_CURVE('E382',#160,#591,#773,.T.);
#775=ORIENTED_EDGE('',*,*,#774,.F.);
#776=ORIENTED_EDGE('',*,*,#161,.F.);
#777=ORIENTED_EDGE('',*,*,#757,.T.);
#778=EDGE_LOOP('',(#769,#775,#776,#777));
#779=FACE_BOUND('',#778,.T.);
#780=ADVANCED_FACE('F485',(#779),#768,.F.);
#781=CARTESIAN_POINT('',(-23.619903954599,4.7625,0.374711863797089));
#782=DIRECTION('',(0.707106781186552,0.,0.707106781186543));
#783=DIRECTION('',(0.707106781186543,0.,-0.707106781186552));
#784=AXIS2_PLACEMENT_3D('',#781,#782,#783);
#785=PLANE('',#784);
#786=ORIENTED_EDGE('',*,*,#592,.T.);
#787=DIRECTION('',(0.,-1.,0.));
#788=VECTOR('',#787,1.);
#789=CARTESIAN_POINT('',(-30.0375960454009,4.7625,6.79240395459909));
#790=LINE('',#789,#788);
#791=EDGE_CURVE('E379',#168,#583,#790,.T.);
#792=ORIENTED_EDGE('',*,*,#791,.F.);
#793=ORIENTED_EDGE('',*,*,#169,.F.);
#794=ORIENTED_EDGE('',*,*,#774,.T.);
#795=EDGE_LOOP('',(#786,#792,#793,#794));
#796=FACE_BOUND('',#795,.T.);
#797=ADVANCED_FACE('F481',(#796),#785,.F.);
#798=CARTESIAN_POINT('',(-26.67,4.7625,10.16));
#799=DIRECTION('',(0.,-1.,0.));
#800=DIRECTION('',(0.,0.,-1.));
#801=AXIS2_PLACEMENT_3D('',#798,#799,#800);
#802=CYLINDRICAL_SURFACE('',#801,4.7625);
#803=ORIENTED_EDGE('',*,*,#584,.T.);
#804=DIRECTION('',(0.,-1.,0.));
#805=VECTOR('',#804,1.);
#806=CARTESIAN_POINT('',(-30.0375960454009,4.7625,13.5275960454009));
#807=LINE('',#806,#805);
#808=EDGE_CURVE('E376',#177,#574,#807,.T.);
#809=ORIENTED_EDGE('',*,*,#808,.F.);
#810=ORIENTED_EDGE('',*,*,#178,.F.);
#811=ORIENTED_EDGE('',*,*,#791,.T.);
#812=EDGE_LOOP('',(#803,#809,#810,#811));
#813=FACE_BOUND('',#812,.T.);
#814=ADVANCED_FACE('F476',(#813),#802,.T.);
#815=CARTESIAN_POINT('',(-30.0375960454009,4.7625,13.5275960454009));
#816=DIRECTION('',(0.707106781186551,0.,-0.707106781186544));
#817=DIRECTION('',(-0.707106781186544,0.,-0.707106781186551));
#818=AXIS2_PLACEMENT_3D('',#815,#816,#817);
#819=PLANE('',#818);
#820=ORIENTED_EDGE('',*,*,#575,.T.);
#821=DIRECTION('',(0.,-1.,0.));
#822=VECTOR('',#821,1.);
#823=CARTESIAN_POINT('',(-23.619903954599,4.7625,19.9452881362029));
#824=LINE('',#823,#822);
#825=EDGE_CURVE('E373',#185,#566,#824,.T.);
#826=ORIENTED_EDGE('',*,*,#825,.F.);
#827=ORIENTED_EDGE('',*,*,#186,.F.);
#828=ORIENTED_EDGE('',*,*,#808,.T.);
#829=EDGE_LOOP('',(#820,#826,#827,#828));
#830=FACE_BOUND('',#829,.T.);
#831=ADVANCED_FACE('F470',(#830),#819,.F.);
#832=CARTESIAN_POINT('',(-18.1161926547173,4.7625,14.4415768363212));
#833=DIRECTION('',(0.,-1.,0.));
#834=DIRECTION('',(0.,0.,-1.));
#835=AXIS2_PLACEMENT_3D('',#832,#833,#834);
#836=CYLINDRICAL_SURFACE('',#835,7.78342316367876);
#837=ORIENTED_EDGE('',*,*,#567,.T.);
#838=DIRECTION('',(0.,-1.,0.));
#839=VECTOR('',#838,1.);
#840=CARTESIAN_POINT('',(-18.1161926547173,4.7625,22.225));
#841=LINE('',#840,#839);
#842=EDGE_CURVE('E370',#194,#557,#841,.T.);
#843=ORIENTED_EDGE('',*,*,#842,.F.);
#844=ORIENTED_EDGE('',*,*,#195,.F.);
#845=ORIENTED_EDGE('',*,*,#825,.T.);
#846=EDGE_LOOP('',(#837,#843,#844,#845));
#847=FACE_BOUND('',#846,.T.);
#848=ADVANCED_FACE('F466',(#847),#836,.T.);
#849=CARTESIAN_POINT('',(-18.1161926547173,4.7625,22.225));
#850=DIRECTION('',(0.,0.,-1.));
#851=DIRECTION('',(-1.,0.,0.));
#852=AXIS2_PLACEMENT_3D('',#849,#850,#851);
#853=PLANE('',#852);
#854=ORIENTED_EDGE('',*,*,#558,.T.);
#855=DIRECTION('',(0.,-1.,0.));
#856=VECTOR('',#855,1.);
#857=CARTESIAN_POINT('',(26.67,4.7625,22.225));
#858=LINE('',#857,#856);
#859=EDGE_CURVE('E367',#202,#549,#858,.T.);
#860=ORIENTED_EDGE('',*,*,#859,.F.);
#861=ORIENTED_EDGE('',*,*,#203,.F.);
#862=ORIENTED_EDGE('',*,*,#842,.T.);
#863=EDGE_LOOP('',(#854,#860,#861,#862));
#864=FACE_BOUND('',#863,.T.);
#865=ADVANCED_FACE('F461',(#864),#853,.F.);
#866=CARTESIAN_POINT('',(26.67,4.7625,17.4625));
#867=DIRECTION('',(0.,-1.,0.));
#868=DIRECTION('',(0.,0.,-1.));
#869=AXIS2_PLACEMENT_3D('',#866,#867,#868);
#870=CYLINDRICAL_SURFACE('',#869,4.7625);
#871=ORIENTED_EDGE('',*,*,#550,.T.);
#872=DIRECTION('',(0.,-1.,0.));
#873=VECTOR('',#872,1.);
#874=CARTESIAN_POINT('',(30.037596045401,4.7625,14.0949039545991));
#875=LINE('',#874,#873);
#876=EDGE_CURVE('E364',#211,#540,#875,.T.);
#877=ORIENTED_EDGE('',*,*,#876,.F.);
#878=ORIENTED_EDGE('',*,*,#212,.F.);
#879=ORIENTED_EDGE('',*,*,#859,.T.);
#880=EDGE_LOOP('',(#871,#877,#878,#879));
#881=FACE_BOUND('',#880,.T.);
#882=ADVANCED_FACE('F455',(#881),#870,.T.);
#883=CARTESIAN_POINT('',(23.619903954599,4.7625,7.67721186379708));
#884=DIRECTION('',(-0.707106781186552,0.,0.707106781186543));
#885=DIRECTION('',(0.707106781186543,0.,0.707106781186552));
#886=AXIS2_PLACEMENT_3D('',#883,#884,#885);
#887=PLANE('',#886);
#888=ORIENTED_EDGE('',*,*,#541,.T.);
#889=DIRECTION('',(0.,-1.,0.));
#890=VECTOR('',#889,1.);
#891=CARTESIAN_POINT('',(23.619903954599,4.7625,7.67721186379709));
#892=LINE('',#891,#890);
#893=EDGE_CURVE('E361',#219,#532,#892,.T.);
#894=ORIENTED_EDGE('',*,*,#893,.F.);
#895=ORIENTED_EDGE('',*,*,#220,.F.);
#896=ORIENTED_EDGE('',*,*,#876,.T.);
#897=EDGE_LOOP('',(#888,#894,#895,#896));
#898=FACE_BOUND('',#897,.T.);
#899=ADVANCED_FACE('F451',(#898),#887,.F.);
#900=CARTESIAN_POINT('',(26.9875,4.7625,4.30961581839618));
#901=DIRECTION('',(0.,-1.,0.));
#902=DIRECTION('',(0.,0.,-1.));
#903=AXIS2_PLACEMENT_3D('',#900,#901,#902);
#904=CYLINDRICAL_SURFACE('',#903,4.7625);
#905=ORIENTED_EDGE('',*,*,#533,.T.);
#906=DIRECTION('',(0.,-1.,0.));
#907=VECTOR('',#906,1.);
#908=CARTESIAN_POINT('',(22.225,4.7625,4.30961581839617));
#909=LINE('',#908,#907);
#910=EDGE_CURVE('E358',#228,#523,#909,.T.);
#911=ORIENTED_EDGE('',*,*,#910,.F.);
#912=ORIENTED_EDGE('',*,*,#229,.F.);
#913=ORIENTED_EDGE('',*,*,#893,.T.);
#914=EDGE_LOOP('',(#905,#911,#912,#913));
#915=FACE_BOUND('',#914,.T.);
#916=ADVANCED_FACE('F446',(#915),#904,.F.);
#917=CARTESIAN_POINT('',(22.225,4.7625,4.30961581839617));
#918=DIRECTION('',(-1.,0.,0.));
#919=DIRECTION('',(0.,0.,1.));
#920=AXIS2_PLACEMENT_3D('',#917,#918,#919);
#921=PLANE('',#920);
#922=ORIENTED_EDGE('',*,*,#524,.T.);
#923=DIRECTION('',(0.,-1.,0.));
#924=VECTOR('',#923,1.);
#925=CARTESIAN_POINT('',(22.225,4.7625,-27.94));
#926=LINE('',#925,#924);
#927=EDGE_CURVE('E355',#236,#515,#926,.T.);
#928=ORIENTED_EDGE('',*,*,#927,.F.);
#929=ORIENTED_EDGE('',*,*,#237,.F.);
#930=ORIENTED_EDGE('',*,*,#910,.T.);
#931=EDGE_LOOP('',(#922,#928,#929,#930));
#932=FACE_BOUND('',#931,.T.);
#933=ADVANCED_FACE('F440',(#932),#921,.F.);
#934=CARTESIAN_POINT('',(17.4625,4.7625,-27.94));
#935=DIRECTION('',(0.,-1.,0.));
#936=DIRECTION('',(0.,0.,-1.));
#937=AXIS2_PLACEMENT_3D('',#934,#935,#936);
#938=CYLINDRICAL_SURFACE('',#937,4.7625);
#939=ORIENTED_EDGE('',*,*,#516,.T.);
#940=DIRECTION('',(0.,-1.,0.));
#941=VECTOR('',#940,1.);
#942=CARTESIAN_POINT('',(14.0949039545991,4.7625,-31.3075960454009));
#943=LINE('',#942,#941);
#944=EDGE_CURVE('E352',#245,#506,#943,.T.);
#945=ORIENTED_EDGE('',*,*,#944,.F.);
#946=ORIENTED_EDGE('',*,*,#246,.F.);
#947=ORIENTED_EDGE('',*,*,#927,.T.);
#948=EDGE_LOOP('',(#939,#945,#946,#947));
#949=FACE_BOUND('',#948,.T.);
#950=ADVANCED_FACE('F436',(#949),#938,.T.);
#951=CARTESIAN_POINT('',(8.48224387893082,4.7625,-25.6949359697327));
#952=DIRECTION('',(0.707106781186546,0.,0.707106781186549));
#953=DIRECTION('',(0.707106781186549,0.,-0.707106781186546));
#954=AXIS2_PLACEMENT_3D('',#951,#952,#953);
#955=PLANE('',#954);
#956=ORIENTED_EDGE('',*,*,#507,.T.);
#957=ORIENTED_EDGE('',*,*,#674,.F.);
#958=ORIENTED_EDGE('',*,*,#252,.F.);
#959=ORIENTED_EDGE('',*,*,#944,.T.);
#960=EDGE_LOOP('',(#956,#957,#958,#959));
#961=FACE_BOUND('',#960,.T.);
#962=ADVANCED_FACE('F431',(#961),#955,.F.);
#963=CARTESIAN_POINT('',(-8.89,4.7625,-17.78));
#964=DIRECTION('',(0.,-1.,0.));
#965=DIRECTION('',(0.,0.,-1.));
#966=AXIS2_PLACEMENT_3D('',#963,#964,#965);
#967=CYLINDRICAL_SURFACE('',#966,3.175);
#968=ORIENTED_EDGE('',*,*,#437,.F.);
#969=DIRECTION('',(0.,-1.,0.));
#970=VECTOR('',#969,1.);
#971=CARTESIAN_POINT('',(-8.88999999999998,4.7625,-20.955));
#972=LINE('',#971,#970);
#973=EDGE_CURVE('E212',#262,#427,#972,.T.);
#974=ORIENTED_EDGE('',*,*,#973,.F.);
#975=ORIENTED_EDGE('',*,*,#265,.T.);
#976=DIRECTION('',(0.,-1.,0.));
#977=VECTOR('',#976,1.);
#978=CARTESIAN_POINT('',(-12.065,4.7625,-17.78));
#979=LINE('',#978,#977);
#980=EDGE_CURVE('E211',#264,#436,#979,.T.);
#981=ORIENTED_EDGE('',*,*,#980,.T.);
#982=EDGE_LOOP('',(#968,#974,#975,#981));
#983=FACE_BOUND('',#982,.T.);
#984=ADVANCED_FACE('F210',(#983),#967,.F.);
#985=CARTESIAN_POINT('',(-12.065,4.7625,17.78));
#986=DIRECTION('',(1.,0.,0.));
#987=DIRECTION('',(0.,0.,-1.));
#988=AXIS2_PLACEMENT_3D('',#985,#986,#987);
#989=PLANE('',#988);
#990=ORIENTED_EDGE('',*,*,#445,.F.);
#991=ORIENTED_EDGE('',*,*,#980,.F.);
#992=ORIENTED_EDGE('',*,*,#322,.T.);
#993=DIRECTION('',(0.,-1.,0.));
#994=VECTOR('',#993,1.);
#995=CARTESIAN_POINT('',(-12.065,4.7625,17.78));
#996=LINE('',#995,#994);
#997=EDGE_CURVE('E225',#315,#444,#996,.T.);
#998=ORIENTED_EDGE('',*,*,#997,.T.);
#999=EDGE_LOOP('',(#990,#991,#992,#998));
#1000=FACE_BOUND('',#999,.T.);
#1001=ADVANCED_FACE('F220',(#1000),#989,.T.);
#1002=CARTESIAN_POINT('',(-8.89,4.7625,17.78));
#1003=DIRECTION('',(0.,-1.,0.));
#1004=DIRECTION('',(0.,0.,-1.));
#1005=AXIS2_PLACEMENT_3D('',#1002,#1003,#1004);
#1006=CYLINDRICAL_SURFACE('',#1005,3.175);
#1007=ORIENTED_EDGE('',*,*,#454,.F.);
#1008=ORIENTED_EDGE('',*,*,#997,.F.);
#1009=ORIENTED_EDGE('',*,*,#316,.T.);
#1010=DIRECTION('',(0.,-1.,0.));
#1011=VECTOR('',#1010,1.);
#1012=CARTESIAN_POINT('',(-8.88999999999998,4.7625,20.955));
#1013=LINE('',#1012,#1011);
#1014=EDGE_CURVE('E273',#306,#453,#1013,.T.);
#1015=ORIENTED_EDGE('',*,*,#1014,.T.);
#1016=EDGE_LOOP('',(#1007,#1008,#1009,#1015));
#1017=FACE_BOUND('',#1016,.T.);
#1018=ADVANCED_FACE('F585',(#1017),#1006,.F.);
#1019=CARTESIAN_POINT('',(-8.88999999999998,4.7625,20.955));
#1020=DIRECTION('',(0.,0.,-1.));
#1021=DIRECTION('',(-1.,0.,0.));
#1022=AXIS2_PLACEMENT_3D('',#1019,#1020,#1021);
#1023=PLANE('',#1022);
#1024=ORIENTED_EDGE('',*,*,#462,.F.);
#1025=ORIENTED_EDGE('',*,*,#1014,.F.);
#1026=ORIENTED_EDGE('',*,*,#307,.T.);
#1027=DIRECTION('',(0.,-1.,0.));
#1028=VECTOR('',#1027,1.);
#1029=CARTESIAN_POINT('',(8.88999999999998,4.7625,20.955));
#1030=LINE('',#1029,#1028);
#1031=EDGE_CURVE('E271',#298,#461,#1030,.T.);
#1032=ORIENTED_EDGE('',*,*,#1031,.T.);
#1033=EDGE_LOOP('',(#1024,#1025,#1026,#1032));
#1034=FACE_BOUND('',#1033,.T.);
#1035=ADVANCED_FACE('F591',(#1034),#1023,.T.);
#1036=CARTESIAN_POINT('',(8.89,4.7625,17.78));
#1037=DIRECTION('',(0.,-1.,0.));
#1038=DIRECTION('',(0.,0.,-1.));
#1039=AXIS2_PLACEMENT_3D('',#1036,#1037,#1038);
#1040=CYLINDRICAL_SURFACE('',#1039,3.175);
#1041=ORIENTED_EDGE('',*,*,#471,.F.);
#1042=ORIENTED_EDGE('',*,*,#1031,.F.);
#1043=ORIENTED_EDGE('',*,*,#299,.T.);
#1044=DIRECTION('',(0.,-1.,0.));
#1045=VECTOR('',#1044,1.);
#1046=CARTESIAN_POINT('',(12.065,4.7625,17.78));
#1047=LINE('',#1046,#1045);
#1048=EDGE_CURVE('E269',#289,#470,#1047,.T.);
#1049=ORIENTED_EDGE('',*,*,#1048,.T.);
#1050=EDGE_LOOP('',(#1041,#1042,#1043,#1049));
#1051=FACE_BOUND('',#1050,.T.);
#1052=ADVANCED_FACE('F599',(#1051),#1040,.F.);
#1053=CARTESIAN_POINT('',(12.065,4.7625,17.78));
#1054=DIRECTION('',(-1.,0.,0.));
#1055=DIRECTION('',(0.,0.,1.));
#1056=AXIS2_PLACEMENT_3D('',#1053,#1054,#1055);
#1057=PLANE('',#1056);
#1058=ORIENTED_EDGE('',*,*,#479,.F.);
#1059=ORIENTED_EDGE('',*,*,#1048,.F.);
#1060=ORIENTED_EDGE('',*,*,#290,.T.);
#1061=DIRECTION('',(0.,-1.,0.));
#1062=VECTOR('',#1061,1.);
#1063=CARTESIAN_POINT('',(12.065,4.7625,-17.78));
#1064=LINE('',#1063,#1062);
#1065=EDGE_CURVE('E267',#281,#478,#1064,.T.);
#1066=ORIENTED_EDGE('',*,*,#1065,.T.);
#1067=EDGE_LOOP('',(#1058,#1059,#1060,#1066));
#1068=FACE_BOUND('',#1067,.T.);
#1069=ADVANCED_FACE('F607',(#1068),#1057,.T.);
#1070=CARTESIAN_POINT('',(8.89,4.7625,-17.78));
#1071=DIRECTION('',(0.,-1.,0.));
#1072=DIRECTION('',(0.,0.,-1.));
#1073=AXIS2_PLACEMENT_3D('',#1070,#1071,#1072);
#1074=CYLINDRICAL_SURFACE('',#1073,3.175);
#1075=ORIENTED_EDGE('',*,*,#486,.F.);
#1076=ORIENTED_EDGE('',*,*,#1065,.F.);
#1077=ORIENTED_EDGE('',*,*,#282,.T.);
#1078=DIRECTION('',(0.,-1.,0.));
#1079=VECTOR('',#1078,1.);
#1080=CARTESIAN_POINT('',(8.88999999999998,4.7625,-20.955));
#1081=LINE('',#1080,#1079);
#1082=EDGE_CURVE('E50',#272,#425,#1081,.T.);
#1083=ORIENTED_EDGE('',*,*,#1082,.T.);
#1084=EDGE_LOOP('',(#1075,#1076,#1077,#1083));
#1085=FACE_BOUND('',#1084,.T.);
#1086=ADVANCED_FACE('F615',(#1085),#1074,.F.);
#1087=CARTESIAN_POINT('',(-8.88999999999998,4.7625,-20.955));
#1088=DIRECTION('',(0.,0.,1.));
#1089=DIRECTION('',(1.,0.,0.));
#1090=AXIS2_PLACEMENT_3D('',#1087,#1088,#1089);
#1091=PLANE('',#1090);
#1092=ORIENTED_EDGE('',*,*,#428,.F.);
#1093=ORIENTED_EDGE('',*,*,#1082,.F.);
#1094=ORIENTED_EDGE('',*,*,#273,.T.);
#1095=ORIENTED_EDGE('',*,*,#973,.T.);
#1096=EDGE_LOOP('',(#1092,#1093,#1094,#1095));
#1097=FACE_BOUND('',#1096,.T.);
#1098=ADVANCED_FACE('F623',(#1097),#1091,.T.);
#1099=CARTESIAN_POINT('',(-16.8275,4.7625,16.8275));
#1100=DIRECTION('',(0.,1.,0.));
#1101=DIRECTION('',(0.,0.,1.));
#1102=AXIS2_PLACEMENT_3D('',#1099,#1100,#1101);
#1103=CYLINDRICAL_SURFACE('',#1102,2.80669999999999);
#1104=ORIENTED_EDGE('',*,*,#652,.F.);
#1105=EDGE_LOOP('',(#1104));
#1106=FACE_BOUND('',#1105,.T.);
#1107=ORIENTED_EDGE('',*,*,#333,.T.);
#1108=EDGE_LOOP('',(#1107));
#1109=FACE_BOUND('',#1108,.T.);
#1110=ADVANCED_FACE('F631',(#1106,#1109),#1103,.F.);
#1111=CARTESIAN_POINT('',(16.8275,4.7625,-16.8275));
#1112=DIRECTION('',(0.,1.,0.));
#1113=DIRECTION('',(0.,0.,1.));
#1114=AXIS2_PLACEMENT_3D('',#1111,#1112,#1113);
#1115=CYLINDRICAL_SURFACE('',#1114,2.80669999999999);
#1116=ORIENTED_EDGE('',*,*,#416,.F.);
#1117=EDGE_LOOP('',(#1116));
#1118=FACE_BOUND('',#1117,.T.);
#1119=ORIENTED_EDGE('',*,*,#97,.T.);
#1120=EDGE_LOOP('',(#1119));
#1121=FACE_BOUND('',#1120,.T.);
#1122=ADVANCED_FACE('F638',(#1118,#1121),#1115,.F.);
#1123=CARTESIAN_POINT('',(16.8275,4.7625,16.8275));
#1124=DIRECTION('',(0.,1.,0.));
#1125=DIRECTION('',(0.,0.,1.));
#1126=AXIS2_PLACEMENT_3D('',#1123,#1124,#1125);
#1127=CYLINDRICAL_SURFACE('',#1126,2.80669999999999);
#1128=ORIENTED_EDGE('',*,*,#405,.F.);
#1129=EDGE_LOOP('',(#1128));
#1130=FACE_BOUND('',#1129,.T.);
#1131=ORIENTED_EDGE('',*,*,#86,.T.);
#1132=EDGE_LOOP('',(#1131));
#1133=FACE_BOUND('',#1132,.T.);
#1134=ADVANCED_FACE('F646',(#1130,#1133),#1127,.F.);
#1135=CARTESIAN_POINT('',(-16.8275,4.7625,-16.8275));
#1136=DIRECTION('',(0.,1.,0.));
#1137=DIRECTION('',(0.,0.,1.));
#1138=AXIS2_PLACEMENT_3D('',#1135,#1136,#1137);
#1139=CYLINDRICAL_SURFACE('',#1138,2.80669999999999);
#1140=ORIENTED_EDGE('',*,*,#394,.F.);
#1141=EDGE_LOOP('',(#1140));
#1142=FACE_BOUND('',#1141,.T.);
#1143=ORIENTED_EDGE('',*,*,#75,.T.);
#1144=EDGE_LOOP('',(#1143));
#1145=FACE_BOUND('',#1144,.T.);
#1146=ADVANCED_FACE('F654',(#1142,#1145),#1139,.F.);
#1147=CARTESIAN_POINT('',(26.67,4.7625,17.4625));
#1148=DIRECTION('',(0.,1.,0.));
#1149=DIRECTION('',(0.,0.,1.));
#1150=AXIS2_PLACEMENT_3D('',#1147,#1148,#1149);
#1151=CYLINDRICAL_SURFACE('',#1150,2.45744999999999);
#1152=ORIENTED_EDGE('',*,*,#383,.F.);
#1153=EDGE_LOOP('',(#1152));
#1154=FACE_BOUND('',#1153,.T.);
#1155=ORIENTED_EDGE('',*,*,#64,.T.);
#1156=EDGE_LOOP('',(#1155));
#1157=FACE_BOUND('',#1156,.T.);
#1158=ADVANCED_FACE('F662',(#1154,#1157),#1151,.F.);
#1159=CARTESIAN_POINT('',(-26.67,4.7625,10.16));
#1160=DIRECTION('',(0.,1.,0.));
#1161=DIRECTION('',(0.,0.,1.));
#1162=AXIS2_PLACEMENT_3D('',#1159,#1160,#1161);
#1163=CYLINDRICAL_SURFACE('',#1162,2.45744999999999);
#1164=ORIENTED_EDGE('',*,*,#372,.F.);
#1165=EDGE_LOOP('',(#1164));
#1166=FACE_BOUND('',#1165,.T.);
#1167=ORIENTED_EDGE('',*,*,#53,.T.);
#1168=EDGE_LOOP('',(#1167));
#1169=FACE_BOUND('',#1168,.T.);
#1170=ADVANCED_FACE('F670',(#1166,#1169),#1163,.F.);
#1171=CARTESIAN_POINT('',(17.4625,4.7625,-27.94));
#1172=DIRECTION('',(0.,1.,0.));
#1173=DIRECTION('',(0.,0.,1.));
#1174=AXIS2_PLACEMENT_3D('',#1171,#1172,#1173);
#1175=CYLINDRICAL_SURFACE('',#1174,2.45744999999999);
#1176=ORIENTED_EDGE('',*,*,#361,.F.);
#1177=EDGE_LOOP('',(#1176));
#1178=FACE_BOUND('',#1177,.T.);
#1179=ORIENTED_EDGE('',*,*,#42,.T.);
#1180=EDGE_LOOP('',(#1179));
#1181=FACE_BOUND('',#1180,.T.);
#1182=ADVANCED_FACE('F679',(#1178,#1181),#1175,.F.);
#1183=CARTESIAN_POINT('',(-17.4625,4.7625,-27.94));
#1184=DIRECTION('',(0.,1.,0.));
#1185=DIRECTION('',(0.,0.,1.));
#1186=AXIS2_PLACEMENT_3D('',#1183,#1184,#1185);
#1187=CYLINDRICAL_SURFACE('',#1186,2.45744999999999);
#1188=ORIENTED_EDGE('',*,*,#350,.F.);
#1189=EDGE_LOOP('',(#1188));
#1190=FACE_BOUND('',#1189,.T.);
#1191=ORIENTED_EDGE('',*,*,#31,.T.);
#1192=EDGE_LOOP('',(#1191));
#1193=FACE_BOUND('',#1192,.T.);
#1194=ADVANCED_FACE('F687',(#1190,#1193),#1187,.F.);
#1195=CLOSED_SHELL('',(#337,#656,#678,#695,#712,#729,#746,#763,#780,#797,#814,#831,#848,#865,
#882,#899,#916,#933,#950,#962,#984,#1001,#1018,#1035,#1052,#1069,#1086,#1098,#1110,#1122,#1134,
#1146,#1158,#1170,#1182,#1194));
#1196=MANIFOLD_SOLID_BREP('B2',#1195);
#1197=ADVANCED_BREP_SHAPE_REPRESENTATION('',(#18,#1196),#14);
#1198=SHAPE_DEFINITION_REPRESENTATION(#9,#1197);
ENDSEC;
END-ISO-10303-21;
